VERSION 5.7 ;
  NAMESCASESENSITIVE ON ;
  NOWIREEXTENSIONATPIN ON ;
  DIVIDERCHAR "/" ;
  BUSBITCHARS "[]" ;
UNITS
  DATABASE MICRONS 200 ;
END UNITS

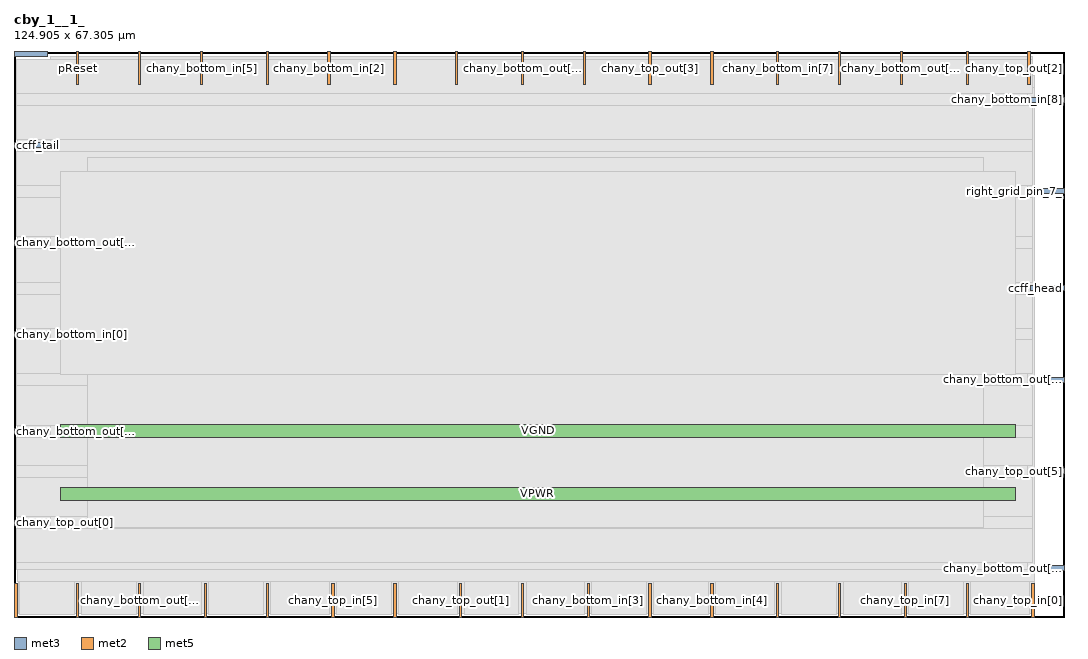
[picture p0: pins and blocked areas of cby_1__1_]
MACRO cby_1__1_
  CLASS BLOCK ;
  FOREIGN cby_1__1_ ;
  ORIGIN 0.000 0.000 ;
  SIZE 124.905 BY 67.305 ;
  PIN ccff_head
    DIRECTION INPUT ;
    PORT
      LAYER met3 ;
        RECT 120.905 38.800 124.905 39.400 ;
    END
  END ccff_head
  PIN ccff_tail
    DIRECTION OUTPUT TRISTATE ;
    PORT
      LAYER met3 ;
        RECT 0.000 55.800 4.000 56.400 ;
    END
  END ccff_tail
  PIN chany_bottom_in[0]
    DIRECTION INPUT ;
    PORT
      LAYER met3 ;
        RECT 0.000 33.360 4.000 33.960 ;
    END
  END chany_bottom_in[0]
  PIN chany_bottom_in[1]
    DIRECTION INPUT ;
    PORT
      LAYER met2 ;
        RECT 0.090 0.000 0.370 4.000 ;
    END
  END chany_bottom_in[1]
  PIN chany_bottom_in[2]
    DIRECTION INPUT ;
    PORT
      LAYER met2 ;
        RECT 37.350 63.305 37.630 67.305 ;
    END
  END chany_bottom_in[2]
  PIN chany_bottom_in[3]
    DIRECTION INPUT ;
    PORT
      LAYER met2 ;
        RECT 68.170 0.000 68.450 4.000 ;
    END
  END chany_bottom_in[3]
  PIN chany_bottom_in[4]
    DIRECTION INPUT ;
    PORT
      LAYER met2 ;
        RECT 82.890 0.000 83.170 4.000 ;
    END
  END chany_bottom_in[4]
  PIN chany_bottom_in[5]
    DIRECTION INPUT ;
    PORT
      LAYER met2 ;
        RECT 22.170 63.305 22.450 67.305 ;
    END
  END chany_bottom_in[5]
  PIN chany_bottom_in[6]
    DIRECTION INPUT ;
    PORT
      LAYER met2 ;
        RECT 113.250 63.305 113.530 67.305 ;
    END
  END chany_bottom_in[6]
  PIN chany_bottom_in[7]
    DIRECTION INPUT ;
    PORT
      LAYER met2 ;
        RECT 90.710 63.305 90.990 67.305 ;
    END
  END chany_bottom_in[7]
  PIN chany_bottom_in[8]
    DIRECTION INPUT ;
    PORT
      LAYER met3 ;
        RECT 120.905 61.240 124.905 61.840 ;
    END
  END chany_bottom_in[8]
  PIN chany_bottom_out[0]
    DIRECTION OUTPUT TRISTATE ;
    PORT
      LAYER met3 ;
        RECT 0.000 21.800 4.000 22.400 ;
    END
  END chany_bottom_out[0]
  PIN chany_bottom_out[1]
    DIRECTION OUTPUT TRISTATE ;
    PORT
      LAYER met2 ;
        RECT 90.710 0.000 90.990 4.000 ;
    END
  END chany_bottom_out[1]
  PIN chany_bottom_out[2]
    DIRECTION OUTPUT TRISTATE ;
    PORT
      LAYER met3 ;
        RECT 0.000 44.240 4.000 44.840 ;
    END
  END chany_bottom_out[2]
  PIN chany_bottom_out[3]
    DIRECTION OUTPUT TRISTATE ;
    PORT
      LAYER met2 ;
        RECT 45.170 63.305 45.450 67.305 ;
    END
  END chany_bottom_out[3]
  PIN chany_bottom_out[4]
    DIRECTION OUTPUT TRISTATE ;
    PORT
      LAYER met2 ;
        RECT 14.810 0.000 15.090 4.000 ;
    END
  END chany_bottom_out[4]
  PIN chany_bottom_out[5]
    DIRECTION OUTPUT TRISTATE ;
    PORT
      LAYER met3 ;
        RECT 120.905 5.480 124.905 6.080 ;
    END
  END chany_bottom_out[5]
  PIN chany_bottom_out[6]
    DIRECTION OUTPUT TRISTATE ;
    PORT
      LAYER met2 ;
        RECT 60.350 63.305 60.630 67.305 ;
    END
  END chany_bottom_out[6]
  PIN chany_bottom_out[7]
    DIRECTION OUTPUT TRISTATE ;
    PORT
      LAYER met3 ;
        RECT 120.905 27.920 124.905 28.520 ;
    END
  END chany_bottom_out[7]
  PIN chany_bottom_out[8]
    DIRECTION OUTPUT TRISTATE ;
    PORT
      LAYER met2 ;
        RECT 105.430 63.305 105.710 67.305 ;
    END
  END chany_bottom_out[8]
  PIN chany_top_in[0]
    DIRECTION INPUT ;
    PORT
      LAYER met2 ;
        RECT 121.070 0.000 121.350 4.000 ;
    END
  END chany_top_in[0]
  PIN chany_top_in[1]
    DIRECTION INPUT ;
    PORT
      LAYER met3 ;
        RECT 0.000 66.680 4.000 67.280 ;
    END
  END chany_top_in[1]
  PIN chany_top_in[2]
    DIRECTION INPUT ;
    PORT
      LAYER met2 ;
        RECT 67.710 63.305 67.990 67.305 ;
    END
  END chany_top_in[2]
  PIN chany_top_in[3]
    DIRECTION INPUT ;
    PORT
      LAYER met2 ;
        RECT 113.250 0.000 113.530 4.000 ;
    END
  END chany_top_in[3]
  PIN chany_top_in[4]
    DIRECTION INPUT ;
    PORT
      LAYER met2 ;
        RECT 29.990 63.305 30.270 67.305 ;
    END
  END chany_top_in[4]
  PIN chany_top_in[5]
    DIRECTION INPUT ;
    PORT
      LAYER met2 ;
        RECT 37.810 0.000 38.090 4.000 ;
    END
  END chany_top_in[5]
  PIN chany_top_in[6]
    DIRECTION INPUT ;
    PORT
      LAYER met2 ;
        RECT 14.810 63.305 15.090 67.305 ;
    END
  END chany_top_in[6]
  PIN chany_top_in[7]
    DIRECTION INPUT ;
    PORT
      LAYER met2 ;
        RECT 105.890 0.000 106.170 4.000 ;
    END
  END chany_top_in[7]
  PIN chany_top_in[8]
    DIRECTION INPUT ;
    PORT
      LAYER met2 ;
        RECT 82.890 63.305 83.170 67.305 ;
    END
  END chany_top_in[8]
  PIN chany_top_out[0]
    DIRECTION OUTPUT TRISTATE ;
    PORT
      LAYER met3 ;
        RECT 0.000 10.920 4.000 11.520 ;
    END
  END chany_top_out[0]
  PIN chany_top_out[1]
    DIRECTION OUTPUT TRISTATE ;
    PORT
      LAYER met2 ;
        RECT 52.990 0.000 53.270 4.000 ;
    END
  END chany_top_out[1]
  PIN chany_top_out[2]
    DIRECTION OUTPUT TRISTATE ;
    PORT
      LAYER met2 ;
        RECT 120.610 63.305 120.890 67.305 ;
    END
  END chany_top_out[2]
  PIN chany_top_out[3]
    DIRECTION OUTPUT TRISTATE ;
    PORT
      LAYER met2 ;
        RECT 75.530 63.305 75.810 67.305 ;
    END
  END chany_top_out[3]
  PIN chany_top_out[4]
    DIRECTION OUTPUT TRISTATE ;
    PORT
      LAYER met2 ;
        RECT 98.070 63.305 98.350 67.305 ;
    END
  END chany_top_out[4]
  PIN chany_top_out[5]
    DIRECTION OUTPUT TRISTATE ;
    PORT
      LAYER met3 ;
        RECT 120.905 17.040 124.905 17.640 ;
    END
  END chany_top_out[5]
  PIN chany_top_out[6]
    DIRECTION OUTPUT TRISTATE ;
    PORT
      LAYER met2 ;
        RECT 29.990 0.000 30.270 4.000 ;
    END
  END chany_top_out[6]
  PIN chany_top_out[7]
    DIRECTION OUTPUT TRISTATE ;
    PORT
      LAYER met2 ;
        RECT 22.630 0.000 22.910 4.000 ;
    END
  END chany_top_out[7]
  PIN chany_top_out[8]
    DIRECTION OUTPUT TRISTATE ;
    PORT
      LAYER met2 ;
        RECT 98.070 0.000 98.350 4.000 ;
    END
  END chany_top_out[8]
  PIN left_grid_pin_1_
    DIRECTION OUTPUT TRISTATE ;
    PORT
      LAYER met2 ;
        RECT 75.530 0.000 75.810 4.000 ;
    END
  END left_grid_pin_1_
  PIN left_grid_pin_5_
    DIRECTION OUTPUT TRISTATE ;
    PORT
      LAYER met2 ;
        RECT 60.350 0.000 60.630 4.000 ;
    END
  END left_grid_pin_5_
  PIN left_grid_pin_9_
    DIRECTION OUTPUT TRISTATE ;
    PORT
      LAYER met2 ;
        RECT 45.170 0.000 45.450 4.000 ;
    END
  END left_grid_pin_9_
  PIN pReset
    DIRECTION INPUT ;
    PORT
      LAYER met2 ;
        RECT 7.450 63.305 7.730 67.305 ;
    END
  END pReset
  PIN prog_clk
    DIRECTION INPUT ;
    PORT
      LAYER met2 ;
        RECT 7.450 0.000 7.730 4.000 ;
    END
  END prog_clk
  PIN right_grid_pin_3_
    DIRECTION OUTPUT TRISTATE ;
    PORT
      LAYER met2 ;
        RECT 52.530 63.305 52.810 67.305 ;
    END
  END right_grid_pin_3_
  PIN right_grid_pin_7_
    DIRECTION OUTPUT TRISTATE ;
    PORT
      LAYER met3 ;
        RECT 120.905 50.360 124.905 50.960 ;
    END
  END right_grid_pin_7_
  PIN VPWR
    DIRECTION INPUT ;
    USE POWER ;
    PORT
      LAYER met5 ;
        RECT 5.520 13.840 119.140 15.440 ;
    END
  END VPWR
  PIN VGND
    DIRECTION INPUT ;
    USE GROUND ;
    PORT
      LAYER met5 ;
        RECT 5.520 21.340 119.140 22.940 ;
    END
  END VGND
  OBS
      LAYER li1 ;
        RECT 5.520 10.795 119.140 54.485 ;
      LAYER met1 ;
        RECT 0.530 0.380 121.370 63.880 ;
      LAYER met2 ;
        RECT 0.370 63.025 7.170 64.445 ;
        RECT 8.010 63.025 14.530 64.445 ;
        RECT 15.370 63.025 21.890 64.445 ;
        RECT 22.730 63.025 29.710 64.445 ;
        RECT 30.550 63.025 37.070 64.445 ;
        RECT 37.910 63.025 44.890 64.445 ;
        RECT 45.730 63.025 52.250 64.445 ;
        RECT 53.090 63.025 60.070 64.445 ;
        RECT 60.910 63.025 67.430 64.445 ;
        RECT 68.270 63.025 75.250 64.445 ;
        RECT 76.090 63.025 82.610 64.445 ;
        RECT 83.450 63.025 90.430 64.445 ;
        RECT 91.270 63.025 97.790 64.445 ;
        RECT 98.630 63.025 105.150 64.445 ;
        RECT 105.990 63.025 112.970 64.445 ;
        RECT 113.810 63.025 120.330 64.445 ;
        RECT 121.170 63.025 121.340 64.445 ;
        RECT 0.370 4.280 121.340 63.025 ;
        RECT 0.650 0.270 7.170 4.280 ;
        RECT 8.010 0.270 14.530 4.280 ;
        RECT 15.370 0.270 22.350 4.280 ;
        RECT 23.190 0.270 29.710 4.280 ;
        RECT 30.550 0.270 37.530 4.280 ;
        RECT 38.370 0.270 44.890 4.280 ;
        RECT 45.730 0.270 52.710 4.280 ;
        RECT 53.550 0.270 60.070 4.280 ;
        RECT 60.910 0.270 67.890 4.280 ;
        RECT 68.730 0.270 75.250 4.280 ;
        RECT 76.090 0.270 82.610 4.280 ;
        RECT 83.450 0.270 90.430 4.280 ;
        RECT 91.270 0.270 97.790 4.280 ;
        RECT 98.630 0.270 105.610 4.280 ;
        RECT 106.450 0.270 112.970 4.280 ;
        RECT 113.810 0.270 120.790 4.280 ;
      LAYER met3 ;
        RECT 4.400 66.280 121.130 66.680 ;
        RECT 0.310 62.240 121.130 66.280 ;
        RECT 0.310 60.840 120.505 62.240 ;
        RECT 0.310 56.800 121.130 60.840 ;
        RECT 4.400 55.400 121.130 56.800 ;
        RECT 0.310 51.360 121.130 55.400 ;
        RECT 0.310 49.960 120.505 51.360 ;
        RECT 0.310 45.240 121.130 49.960 ;
        RECT 4.400 43.840 121.130 45.240 ;
        RECT 0.310 39.800 121.130 43.840 ;
        RECT 0.310 38.400 120.505 39.800 ;
        RECT 0.310 34.360 121.130 38.400 ;
        RECT 4.400 32.960 121.130 34.360 ;
        RECT 0.310 28.920 121.130 32.960 ;
        RECT 0.310 27.520 120.505 28.920 ;
        RECT 0.310 22.800 121.130 27.520 ;
        RECT 4.400 21.400 121.130 22.800 ;
        RECT 0.310 18.040 121.130 21.400 ;
        RECT 0.310 16.640 120.505 18.040 ;
        RECT 0.310 11.920 121.130 16.640 ;
        RECT 4.400 10.520 121.130 11.920 ;
        RECT 0.310 6.480 121.130 10.520 ;
        RECT 0.310 5.630 120.505 6.480 ;
      LAYER met4 ;
        RECT 8.720 10.640 115.320 54.640 ;
      LAYER met5 ;
        RECT 5.520 28.840 119.140 52.940 ;
  END
END cby_1__1_
END LIBRARY

